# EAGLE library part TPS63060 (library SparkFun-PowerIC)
Texas Instruments TPS63060 High Input Buck-Boost Converter. Available in adjustable and fixed output voltage versions. Is packaged in a 10-pin PWSON package measuring about 3 x 3 mm. Datasheet

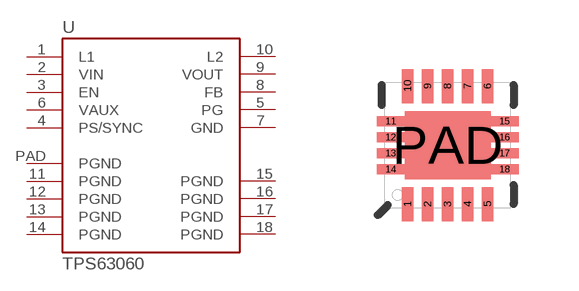
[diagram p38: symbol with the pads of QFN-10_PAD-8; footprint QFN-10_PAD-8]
Designator prefix U

## TPS63060  [QFN-10_PAD-8]
1  L1
2  VIN
3  EN
4  PS/SYNC
5  PG
6  VAUX
7  GND
8  FB
9  VOUT
10  L2
11  PGND
12  PGND
13  PGND
14  PGND
15  PGND
16  PGND
17  PGND
18  PGND
PAD  PGND

## Footprint QFN-10_PAD-8 (pad centres in mm)
smd 0.28 x 0.85: 1 -1,-1.475; 2 -0.5,-1.475; 3 0,-1.475; 4 0.5,-1.475; 5 1,-1.475; 6 1,1.475; 7 0.5,1.475; 8 0,1.475; 9 -0.5,1.475; 10 -1,1.475
smd 0.7 x 0.25: 11 -1.425,0.6; 12 -1.425,0.2; 13 -1.425,-0.2; 14 -1.425,-0.6; 15 1.425,0.6; 16 1.425,0.2; 17 1.425,-0.2; 18 1.425,-0.6
smd 2.15 x 1.7: PAD 0,0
